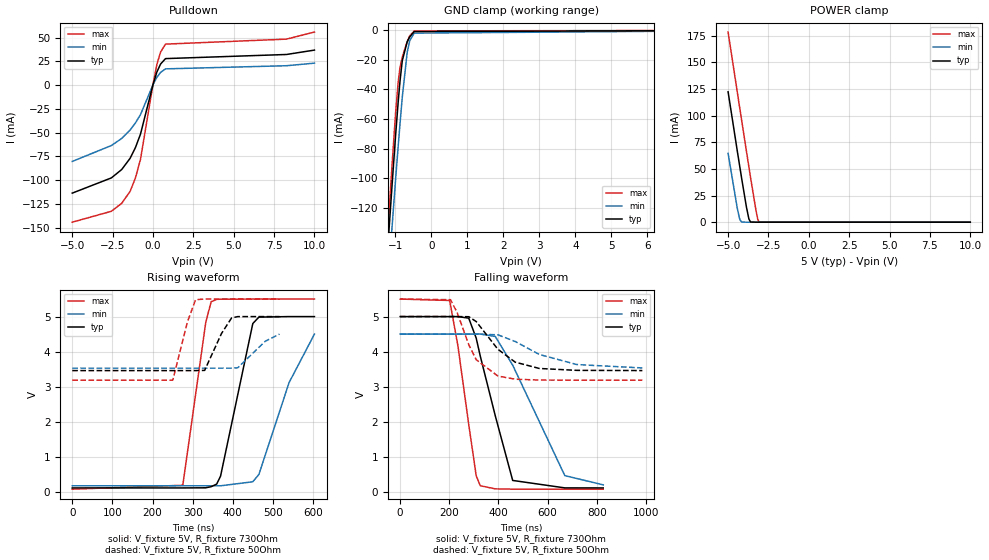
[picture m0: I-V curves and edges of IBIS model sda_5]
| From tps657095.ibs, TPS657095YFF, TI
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|   sda_5 Model
[Model]   sda_5
Model_type   I/O_open_drain
Polarity   Inverting
Vinl=0.4
Vinh=1.2
Vmeas = 2.5
Vref = 5
Cref = 400pF
Rref = 730
|   typ   min   max
|   (nom PVT)   (fast PVT)   (slow PVT)
C_comp   2.994e-12   2.994e-12   3.144e-12
| Where nom  PVT is Nominal Process, 5V, 27C
|   Fast PVT is Strong Process,  5.5V, -40C
|   Slow PVT is Weak Process,   4.5V, 125C
[Voltage Range]   5   4.5   5.5
|Junction Temperature
[Temperature Range]   27   125   -40
[Pullup Reference]   5   4.5   5.5
[Pulldown Reference]   0   0   0
[Power Clamp Reference]   5   4.5   5.5
[GND Clamp Reference]   0   0   0
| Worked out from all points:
|   slope of the pulldown table from 0 to 0.75 V, typ, clamps not added: 27.3 ohm
|   GND clamp passes 1 mA (typ) near -0.48 V on its own axis
|   POWER clamp passes 1 mA (typ) near -3.66 V on its own axis
|   falling waveform, V_fixture 5V, R_fixture 730Ohm: 20-80 % time 106ns typ, 171ns min, 65.1ns max; typ from 5 V to 0.11 V
|   rising waveform, V_fixture 5V, R_fixture 730Ohm: 20-80 % time 54ns typ, 79.1ns min, 37.7ns max; typ from 0.109 V to 5 V
|   falling waveform, V_fixture 5V, R_fixture 50Ohm: 20-80 % time 124ns typ, 181ns min, 87.7ns max; typ from 5 V to 3.46 V
|   rising waveform, V_fixture 5V, R_fixture 50Ohm: 20-80 % time 38.5ns typ, 54.5ns min, 31.2ns max; typ from 3.46 V to 5 V
[Pulldown]
|   Voltage   I(typ)   I(min)   I(max)
-5V       -113.8mA   -80.45mA   -144.4mA
-2.575V   -97.77mA   -63.7mA    -132.9mA
-1.937V   -88.95mA   -56.21mA   -124.5mA
-1.419V   -77.2mA    -47.41mA   -112mA
-1.09V    -65.95mA   -39.99mA   -98.01mA
-775mV    -51.78mA   -31.19mA   -78.29mA
5mV       655.3uA    365.8uA    1.1mA
245mV     13.83mA    8.21mA     21.92mA
472.5mV   22.14mA    13.31mA    34.75mA
778mV     27.79mA    16.99mA    43.04mA
8.271V    32.13mA    20.3mA     48.3mA
10V       36.75mA    23.01mA    55.7mA
[GND Clamp]
|   Voltage   I(typ)   I(min)   I(max)
-5V       -1.753A    -1.649A    -1.865A
-1.4V     -219.3mA   -239.9mA   -214.4mA
-1.184V   -138.6mA   -164.9mA   -127.2mA
-1.089V   -104.8mA   -133.1mA   -91.03mA
-990.5mV  -71.04mA   -100.8mA   -55.9mA
-919mV    -48.52mA   -78.4mA    -34.93mA
-869.5mV  -34.62mA   -63.49mA   -25.27mA
-805mV    -20.5mA    -45.19mA   -18.03mA
-670mV    -7.891mA   -15.08mA   -7.724mA
-599mV    -4.474mA   -7.097mA   -3.773mA
-473.5mV  -827.7uA   -1.883mA   -370.8uA
10V       0A         111.2nA    0A
[POWER Clamp]
|   Voltage   I(typ)   I(min)   I(max)
-5V       122.2mA    64.55mA    178.2mA
-4.438V   67.49mA    13.64mA    122.7mA
-4.303V   54.54mA    4.187mA    109.4mA
-4.248V   49.4mA     1.76mA     104.1mA
-4.15V    40.09mA    159.2uA    94.43mA
-3.865V   14.26mA    76.52nA    66.64mA
-3.71V    2.889mA    33.03nA    51.65mA
-3.61V    172.9uA    30.93nA    42.06mA
-3.272V   0A         25.89nA    10.96mA
-3.163V   0A         24.45nA    2.802mA
-3.091V   0A         23.56nA    279.9uA
10V       0A         0A         0A
[Ramp]
R_load = 730
|   typ   min   max
dV/dt_r   2.93432/5.39753e-08   2.59743/7.93328e-08   3.25542/3.78255e-08
dV/dt_f   2.93432/1.06089e-07   2.59596/1.71275e-07   3.25542/6.50767e-08
[Falling Waveform]
V_fixture = 5V
V_fixture_min = 4.5V
V_fixture_max = 5.5V
R_fixture = 730Ohm
|   Time   V(typ)   V(min)   V(max)
0s        5V         4.5V       5.5V
201.5ns   5V         4.5V       5.46V
235.3ns   5V         4.5V       4.152V
279.1ns   4.955V     4.5V       1.921V
309.5ns   4.385V     4.5V       456.5mV
325.9ns   3.877V     4.503V     173.4mV
387.1ns   2.17V      4.432V     82.66mV
458ns     323.4mV    3.613V     75.06mV
670.2ns   110.8mV    461.2mV    74.3mV
826.6ns   109.5mV    197.1mV    74.3mV
[Rising Waveform]
V_fixture = 5V
V_fixture_min = 4.5V
V_fixture_max = 5.5V
R_fixture = 730Ohm
|   Time   V(typ)   V(min)   V(max)
0s        109.5mV    170.9mV    74.3mV
275.5ns   109.5mV    170.9mV    185.6mV
332.7ns   113.6mV    170.9mV    4.831V
346.1ns   143.9mV    170.9mV    5.423V
360ns     220.4mV    170.9mV    5.492V
369.6ns   445.7mV    170.9mV    5.496V
450ns     4.802V     285.8mV    5.5V
465.2ns   4.985V     496mV      5.5V
540.4ns   5V         3.116V     5.5V
603.6ns   5V         4.5V       5.5V
[Falling Waveform]
V_fixture = 5V
V_fixture_min = 4.5V
V_fixture_max = 5.5V
R_fixture = 50Ohm
|   Time   V(typ)   V(min)   V(max)
0s        5V         4.5V       5.5V
205ns     5V         4.5V       5.482V
232.1ns   5V         4.5V       5.112V
279.5ns   4.996V     4.5V       4.192V
310ns     4.855V     4.5V       3.766V
397.7ns   4.067V     4.48V      3.303V
468.3ns   3.699V     4.289V     3.213V
566.6ns   3.519V     3.918V     3.188V
719ns     3.465V     3.631V     3.185V
985.9ns   3.459V     3.534V     3.184V
[Rising Waveform]
V_fixture = 5V
V_fixture_min = 4.5V
V_fixture_max = 5.5V
R_fixture = 50Ohm
|   Time   V(typ)   V(min)   V(max)
0s        3.459V     3.528V     3.184V
250.4ns   3.459V     3.528V     3.184V
287.6ns   3.459V     3.528V     4.869V
307.5ns   3.459V     3.528V     5.483V
329.9ns   3.464V     3.528V     5.5V
371.9ns   4.516V     3.528V     5.5V
397.1ns   4.961V     3.528V     5.5V
412.5ns   4.999V     3.539V     5.5V
480.9ns   5V         4.295V     5.5V
516.5ns   5V         4.5V       5.5V
